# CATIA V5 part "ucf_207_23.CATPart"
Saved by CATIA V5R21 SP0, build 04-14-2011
Part number: ucf_207_23
Bounding box of the stored display mesh (mm): x -25.5 to -17.5, y -22.9 to -14.9, z -3.804 to 3.804
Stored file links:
  C:\TPO v2\SharedFS\Outgoing\ucf_207_23.CATPart

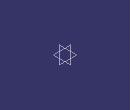
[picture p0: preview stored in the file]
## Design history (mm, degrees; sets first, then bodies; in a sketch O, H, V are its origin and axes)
AxisSystem1: origin (0, 0, 0), X (1, 0, 0), Y (0, 1, 0), Z (0, 0, 1)
Body1 "ucf_207_23" (main body)
  Solid1: solid without history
